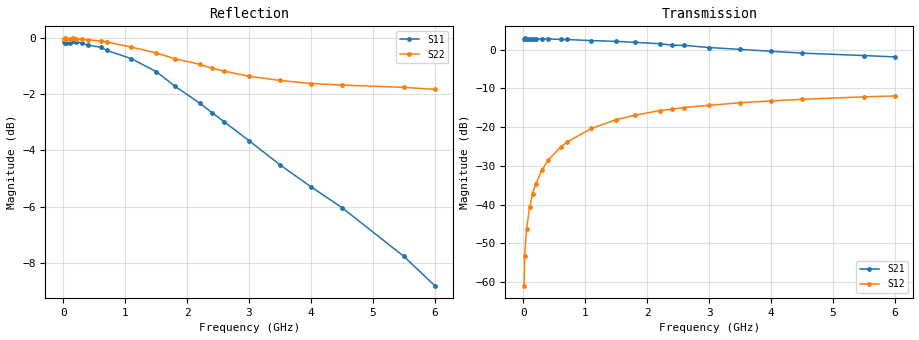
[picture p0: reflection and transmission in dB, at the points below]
! SIEMENS Discrete & RF Semiconductors
! BFY180
! Si NPN RF Bipolar Junction Transistor in MICRO-X
! VCE = 6 V  IC = 0.4 mA
! Common Emitter S-Parameters:  May  1997
# GHz  S  MA  R  50
!  f  S11  S21  S12  S22
! GHz  MAG  ANG  MAG  ANG  MAG  ANG  MAG  ANG
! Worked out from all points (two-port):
!   36 points, 10 MHz to 6 GHz, reference 50 ohm
!   highest |S21| = 2.91 dB at 20 MHz (marker M1); lowest = -1.9 dB at 6 GHz (marker M2)
!   |S21| within 3 dB of the highest: start of sweep to 3.663 GHz
!   lowest |S11| = -8.8 dB at 6 GHz (marker M3), VSWR 2.14, Z = 27.7 - j18.3 ohm
!   |S11| at or under -10 dB: nowhere
!   |S22| runs from -1.8 to 0.0 dB; largest |S21 - S12| = 1.4
!   S11 on the Smith chart (normalised r, x): 10 MHz: open; 700 MHz: 0.75, -5.37; 1.5 GHz: 0.50, -2.48; 2.4 GHz: 0.50, -1.46; 4 GHz: 0.52, -0.80; 6 GHz: 0.55, -0.37
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0.01  0.9864 -0.2  1.368 179.7  0.0009 82.7  0.9993 -0.2
0.02  0.9798 -0.5  1.398 179.2  0.0022 97.0  0.9999 -0.4
0.05  0.9817 -1.3  1.379 178.1  0.0048 84.2  0.9977 -1.0
0.1  0.9808 -3.0  1.371 176.4  0.0093 89.9  0.9957 -2.2
0.15  0.9873 -4.4  1.382 174.5  0.0139 85.8  1 -3.2
0.2  0.9864 -5.8  1.365 172.3  0.0185 85.2  0.9988 -4.3
0.3  0.9804 -8.7  1.377 168.4  0.0281 83.5  0.9954 -6.4
0.4  0.972 -11.7  1.377 164.6  0.0376 80.9  0.9949 -8.6
0.6  0.9644 -17.6  1.354 156.2  0.0552 76.1  0.9885 -12.8
0.7  0.952 -20.7  1.352 153.3  0.0639 73.1  0.9856 -15.0
1.1  0.9198 -31.3  1.307 138.9  0.0962 64.4  0.9647 -23.2
1.5  0.8724 -42.5  1.278 124.8  0.125 55.5  0.942 -31.1
1.8  0.8222 -50.4  1.243 114.3  0.1425 49.9  0.9199 -36.6
2.2  0.7666 -59.8  1.193 101.1  0.1634 42.5  0.899 -43.6
2.4  0.7374 -64.5  1.144 95.1  0.1711 39.4  0.8848 -46.7
2.6  0.7094 -68.9  1.134 89.3  0.1788 36.4  0.874 -49.7
3  0.6569 -76.7  1.065 78.6  0.1914 30.7  0.8559 -55.6
3.5  0.5948 -85.2  1.008 65.7  0.2063 24.8  0.8412 -62.3
4  0.5436 -93.4  0.953 54.1  0.2181 19.0  0.8307 -69.1
4.5  0.499 -101.0  0.902 43.9  0.2286 13.9  0.8255 -75.9
5.5  0.4085 -117.9  0.839 24.6  0.246 4.0  0.8177 -89.9
6  0.3621 -127.3  0.806 15.8  0.2525 -1.1  0.8109 -96.9
